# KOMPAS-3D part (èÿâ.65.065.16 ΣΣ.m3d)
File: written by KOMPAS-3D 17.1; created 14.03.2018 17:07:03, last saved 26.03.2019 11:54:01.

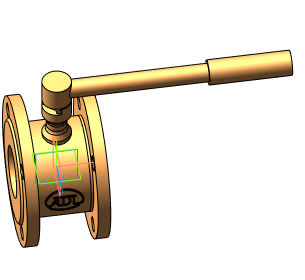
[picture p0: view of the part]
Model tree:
1. Операция без истории:3  (labels: Сталь 20  ГОСТ 1050-2013)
